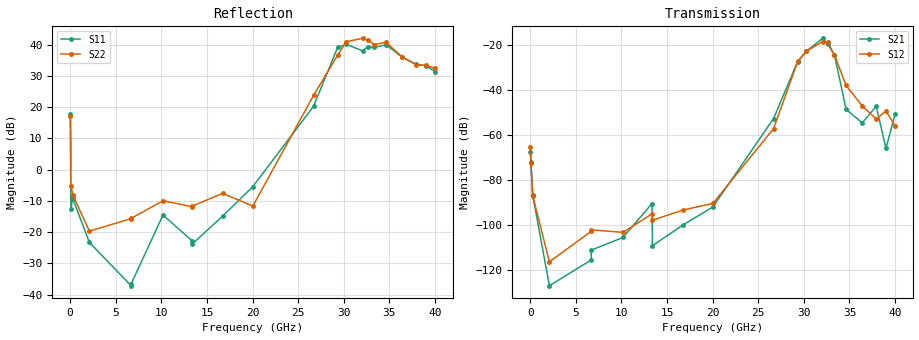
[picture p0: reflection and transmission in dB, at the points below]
!Agilent Technologies,N5230A,US43500312,A.07.50.67
!Agilent N5230A: A.07.50.67
!Date: Thursday, March 05, 2015 11:18:17
!Correction: S11(Full 2 Port(1,2))
!S21(Full 2 Port(1,2))
!S12(Full 2 Port(1,2))
!S22(Full 2 Port(1,2))
!S2P File: Measurements: S11, S21, S12, S22:
# Hz S  dB  R 50
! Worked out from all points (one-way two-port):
!   1600 points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, 34.99 MHz to 40 GHz, reference 50 ohm
!   highest |S21| = -16.97 dB at 32.05 GHz (marker M1); lowest = -126.9 dB at 2.109 GHz (marker M2)
!   lowest |S11| = -37.1 dB at 6.683 GHz (marker M3), VSWR 1.03, Z = 48.7 + j0.555 ohm
!   |S11| at or under -10 dB: 82.08 MHz to 96.96 MHz (14.88 MHz wide, 16.6 % of centre); 324.2 MHz to 17.36 GHz (17.03 GHz wide, 193 % of centre)
!   |S22| runs from -20.8 to 43.1 dB; largest |S21 - S12| = 0.028
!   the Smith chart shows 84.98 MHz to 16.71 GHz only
!   S11 on the Smith chart (normalised r, x): 84.98 MHz: 0.63, -0.13; 284.9 MHz: 0.99, -0.74; 10.18 GHz: 1.32, -0.31; 13.41 GHz: 0.99, +0.13; 16.71 GHz: 1.13, +0.37
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3.499375e7  17.75 -130.8  -67.33 -86.9  -65.37 -105.4  17.10 -127.3
8.498125e7  -12.52 -156.1  -72.03 -148.1  -72.47 -155.3  -5.09 -114.1
2.849312e8  -9.15 -70.7  -86.72 70.7  -86.88 72.6  -8.04 -67.7
2.109475e9  -23.24 12.5  -126.87 -163.9  -116.28 -160.6  -19.66 44.1
6.683331e9  -37.11 155.9  -115.45 -44.8  -102.72 -5.4  -15.66 168.7
6.708325e9  -36.44 178.2  -111.05 -99.1  -102.09 -25.7  -15.57 170.6
1.018246e10  -14.49 -36.3  -105.42 -39.3  -103.17 120.6  -9.92 -20.3
1.335666e10  -22.73 80.1  -90.35 94.0  -94.95 162.9  -11.85 179.2
1.340665e10  -23.71 89.5  -109.10 60.4  -97.76 11.1  -11.63 -177.0
1.670582e10  -14.89 60.1  -99.99 4.8  -93.29 -53.3  -7.58 26.1
2.002999e10  -5.39 24.0  -91.87 4.7  -90.31 -86.9  -11.62 133.6
2.667833e10  20.27 -104.7  -52.59 79.4  -57.08 95.3  23.75 -53.7
2.932767e10  39.14 -134.5  -27.25 -9.6  -27.20 -10.6  36.70 -50.9
3.027743e10  40.11 -163.2  -22.68 -76.5  -22.63 -76.3  40.97 -63.6
3.205199e10  38.03 68.4  -16.97 154.4  -18.40 153.5  42.02 -53.9
3.260185e10  39.31 50.3  -19.40 98.9  -18.68 96.7  41.54 -48.1
3.335166e10  39.14 53.4  -24.33 27.3  -24.33 19.0  40.04 -26.3
3.462634e10  39.96 56.5  -48.50 -93.7  -37.90 -52.0  40.76 0.2
3.64009e10  36.02 115.6  -54.51 110.3  -47.01 4.3  36.06 80.5
3.792552e10  33.74 -159.2  -47.14 95.4  -52.81 149.0  33.60 178.9
3.900025e10  33.27 -97.1  -65.87 94.7  -49.27 104.1  33.37 -108.7
4e10  31.38 -50.6  -50.54 30.6  -55.84 68.6  32.42 -41.4
